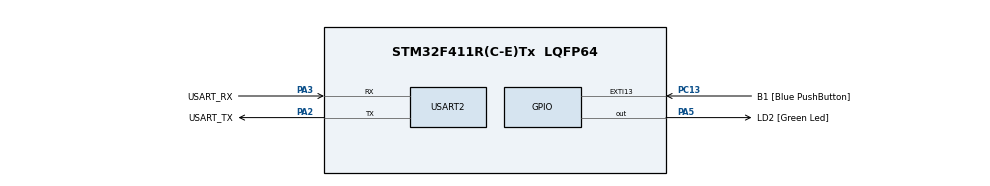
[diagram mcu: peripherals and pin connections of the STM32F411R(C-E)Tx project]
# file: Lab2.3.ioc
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Mcu.Family=STM32F4
Mcu.Name=STM32F411R(C-E)Tx
Mcu.Package=LQFP64
NVIC.PriorityGroup=NVIC_PRIORITYGROUP_0
PA13.GPIO_Label=TMS
PA13.Mode=Serial_Wire
PA13.Signal=SYS_JTMS-SWDIO
PA14.GPIO_Label=TCK
PA14.Mode=Serial_Wire
PA14.Signal=SYS_JTCK-SWCLK
PA2.GPIO_Label=USART_TX
PA2.Mode=Asynchronous
PA2.Signal=USART2_TX
PA3.GPIO_Label=USART_RX
PA3.Mode=Asynchronous
PA3.Signal=USART2_RX
PA5.GPIO_Label=LD2 [Green Led]
PA5.Signal=GPIO_Output
PB3.GPIO_Label=SWO
PB3.Signal=SYS_JTDO-SWO
PC13-ANTI_TAMP.GPIO_Label=B1 [Blue PushButton]
PC13-ANTI_TAMP.GPIO_ModeDefaultEXTI=GPIO_MODE_IT_FALLING
PC13-ANTI_TAMP.Signal=GPXTI13
PC14-OSC32_IN.Mode=LSE-External-Oscillator
PC14-OSC32_IN.Signal=RCC_OSC32_IN
PC15-OSC32_OUT.Mode=LSE-External-Oscillator
PC15-OSC32_OUT.Signal=RCC_OSC32_OUT
PH0\ -\ OSC_IN.Mode=HSE-External-Clock-Source
PH0\ -\ OSC_IN.Signal=RCC_OSC_IN
PH1\ -\ OSC_OUT.Mode=HSE-External-Clock-Source
PH1\ -\ OSC_OUT.Signal=RCC_OSC_OUT
ProjectManager.HeapSize=0x200
ProjectManager.StackSize=0x400
ProjectManager.TargetToolchain=STM32CubeIDE
RCC.48MHZClocksFreq_Value=25000000
RCC.AHBCLKDivider=RCC_SYSCLK_DIV2
RCC.AHBFreq_Value=25000000
RCC.APB1CLKDivider=RCC_HCLK_DIV2
RCC.APB1Freq_Value=12500000
RCC.APB1TimFreq_Value=25000000
RCC.APB2Freq_Value=25000000
RCC.APB2TimFreq_Value=25000000
RCC.CortexFreq_Value=25000000
RCC.FLatency-AdvancedSettings=FLASH_LATENCY_0
RCC.HCLKFreq_Value=25000000
RCC.HSE_VALUE=8000000
RCC.HSI_VALUE=16000000
RCC.PLLM=8
RCC.PLLN=50
RCC.SYSCLKFreq_VALUE=50000000
RCC.SYSCLKSource=RCC_SYSCLKSOURCE_PLLCLK
RCC.VCOOutputFreq_Value=100000000
USART2.VirtualMode=VM_ASYNC
board=NUCLEO-F411RE

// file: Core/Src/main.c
/* USER CODE BEGIN Header */
/**
 ******************************************************************************
 * @file           : main.c
 * @brief          : Main program body
 ******************************************************************************
 * @attention
 *
 * <h2><center>&copy; Copyright (c) 2021 STMicroelectronics.
 * All rights reserved.</center></h2>
 *
 * This software component is licensed by ST under BSD 3-Clause license,
 * the "License"; You may not use this file except in compliance with the
 * License. You may obtain a copy of the License at:
 *                        opensource.org/licenses/BSD-3-Clause
 *
 ******************************************************************************
 */
/* USER CODE END Header */
#include "main.h"

UART_HandleTypeDef huart2;

void SystemClock_Config(void);
static void MX_GPIO_Init(void);
static void MX_USART2_UART_Init(void);

/* USER CODE BEGIN 0 */
_Bool pressed = 0;
int a = 0;
char array[5];
/* USER CODE END 0 */

int main(void) {

	/* MCU Configuration--------------------------------------------------------*/

	/* Reset of all peripherals, Initializes the Flash interface and the Systick. */
	HAL_Init();

	/* Configure the system clock */
	SystemClock_Config();

	/* Initialize all configured peripherals */
	MX_GPIO_Init();
	MX_USART2_UART_Init();

	/* Infinite loop */
	/* USER CODE BEGIN WHILE */
	while (1) {
		if (HAL_GPIO_ReadPin(GPIOC, GPIO_PIN_13) && pressed) // button is released (used to be pressed)
				{
			HAL_Delay(5);
			if (HAL_GPIO_ReadPin(GPIOC, GPIO_PIN_13)) {
				HAL_GPIO_TogglePin(GPIOA, 1 << 5);
				pressed = 0;
			}
		} else if (HAL_GPIO_ReadPin(GPIOC, GPIO_PIN_13) == GPIO_PIN_RESET) // button is pressed
				{
			HAL_Delay(5);
			if (HAL_GPIO_ReadPin(GPIOC, GPIO_PIN_13) == GPIO_PIN_RESET) {
				pressed = 1;
			}
		}
		/* USER CODE END WHILE */

	}
}

void SystemClock_Config(void) {
	RCC_OscInitTypeDef RCC_OscInitStruct = { 0 };
	RCC_ClkInitTypeDef RCC_ClkInitStruct = { 0 };

	/** Configure the main internal regulator output voltage
	 */
	__HAL_RCC_PWR_CLK_ENABLE();
	__HAL_PWR_VOLTAGESCALING_CONFIG(PWR_REGULATOR_VOLTAGE_SCALE1);
	/** Initializes the RCC Oscillators according to the specified parameters
	 * in the RCC_OscInitTypeDef structure.
	 */
	RCC_OscInitStruct.OscillatorType = RCC_OSCILLATORTYPE_HSI;
	RCC_OscInitStruct.HSIState = RCC_HSI_ON;
	RCC_OscInitStruct.HSICalibrationValue = RCC_HSICALIBRATION_DEFAULT;
	RCC_OscInitStruct.PLL.PLLState = RCC_PLL_ON;
	RCC_OscInitStruct.PLL.PLLSource = RCC_PLLSOURCE_HSI;
	RCC_OscInitStruct.PLL.PLLM = 16;
	RCC_OscInitStruct.PLL.PLLN = 336;
	RCC_OscInitStruct.PLL.PLLP = RCC_PLLP_DIV4;
	RCC_OscInitStruct.PLL.PLLQ = 4;
	if (HAL_RCC_OscConfig(&RCC_OscInitStruct) != HAL_OK) {
		Error_Handler();
	}
	/** Initializes the CPU, AHB and APB buses clocks
	 */
	RCC_ClkInitStruct.ClockType = RCC_CLOCKTYPE_HCLK | RCC_CLOCKTYPE_SYSCLK
			| RCC_CLOCKTYPE_PCLK1 | RCC_CLOCKTYPE_PCLK2;
	RCC_ClkInitStruct.SYSCLKSource = RCC_SYSCLKSOURCE_PLLCLK;
	RCC_ClkInitStruct.AHBCLKDivider = RCC_SYSCLK_DIV1;
	RCC_ClkInitStruct.APB1CLKDivider = RCC_HCLK_DIV2;
	RCC_ClkInitStruct.APB2CLKDivider = RCC_HCLK_DIV1;

	if (HAL_RCC_ClockConfig(&RCC_ClkInitStruct, FLASH_LATENCY_2) != HAL_OK) {
		Error_Handler();
	}
}

static void MX_USART2_UART_Init(void) {

	huart2.Instance = USART2;
	huart2.Init.BaudRate = 115200;
	huart2.Init.WordLength = UART_WORDLENGTH_8B;
	huart2.Init.StopBits = UART_STOPBITS_1;
	huart2.Init.Parity = UART_PARITY_NONE;
	huart2.Init.Mode = UART_MODE_TX_RX;
	huart2.Init.HwFlowCtl = UART_HWCONTROL_NONE;
	huart2.Init.OverSampling = UART_OVERSAMPLING_16;
	if (HAL_UART_Init(&huart2) != HAL_OK) {
		Error_Handler();
	}

}

static void MX_GPIO_Init(void) {
	GPIO_InitTypeDef GPIO_InitStruct = { 0 };

	/* GPIO Ports Clock Enable */
	__HAL_RCC_GPIOC_CLK_ENABLE();
	__HAL_RCC_GPIOH_CLK_ENABLE();
	__HAL_RCC_GPIOA_CLK_ENABLE();
	__HAL_RCC_GPIOB_CLK_ENABLE();

	/*Configure GPIO pin Output Level */
	HAL_GPIO_WritePin(LD2_GPIO_Port, LD2_Pin, GPIO_PIN_RESET);

	/*Configure GPIO pin : PC13 */
	GPIO_InitStruct.Pin = GPIO_PIN_13;
	GPIO_InitStruct.Mode = GPIO_MODE_INPUT;
	GPIO_InitStruct.Pull = GPIO_NOPULL;
	HAL_GPIO_Init(GPIOC, &GPIO_InitStruct);

	/*Configure GPIO pin : LD2_Pin */
	GPIO_InitStruct.Pin = LD2_Pin;
	GPIO_InitStruct.Mode = GPIO_MODE_OUTPUT_PP;
	GPIO_InitStruct.Pull = GPIO_NOPULL;
	GPIO_InitStruct.Speed = GPIO_SPEED_FREQ_LOW;
	HAL_GPIO_Init(LD2_GPIO_Port, &GPIO_InitStruct);

}

void Error_Handler(void) {
	__disable_irq();
	while (1) {
	}
}

/************************ (C) COPYRIGHT STMicroelectronics *****END OF FILE****/
